VERSION 5.7 ;
  NOWIREEXTENSIONATPIN ON ;
  DIVIDERCHAR "/" ;
  BUSBITCHARS "[]" ;
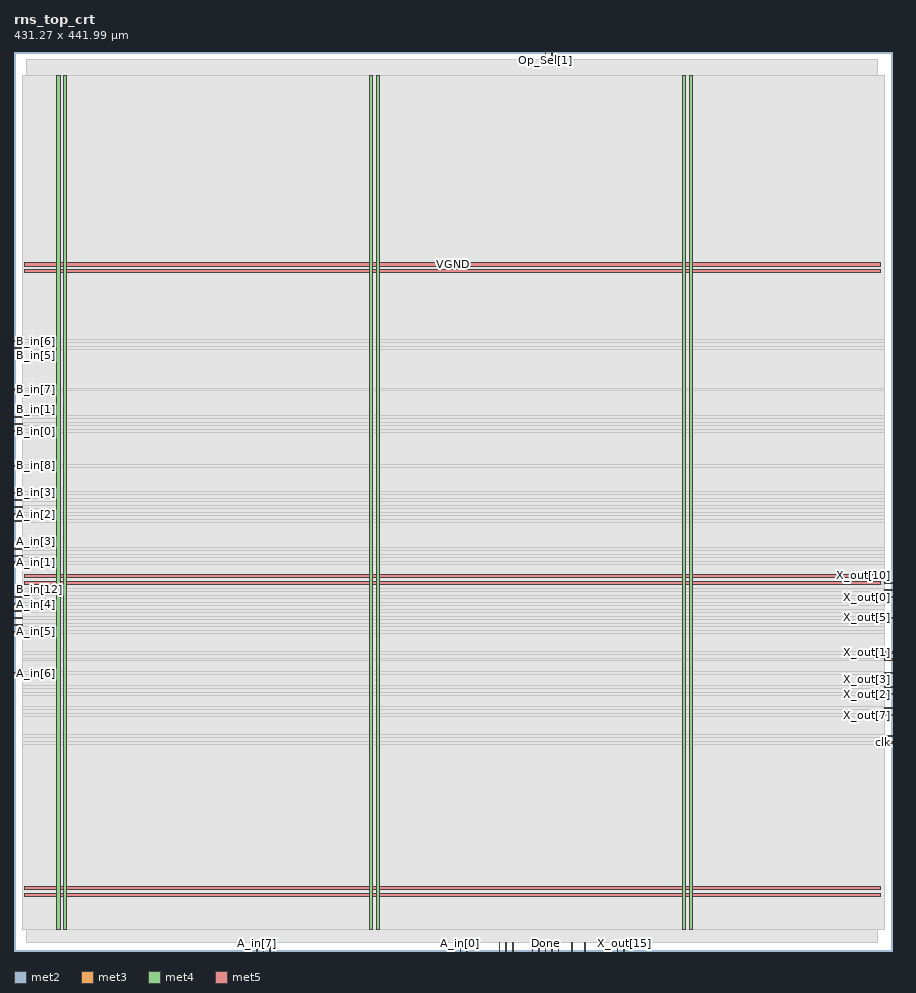
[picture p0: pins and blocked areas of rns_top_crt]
MACRO rns_top_crt
  CLASS BLOCK ;
  FOREIGN rns_top_crt ;
  ORIGIN 0.000 0.000 ;
  SIZE 431.270 BY 441.990 ;
  PIN A_in[0]
    DIRECTION INPUT ;
    USE SIGNAL ;
    ANTENNAGATEAREA 0.631200 ;
    ANTENNADIFFAREA 0.434700 ;
    PORT
      LAYER met2 ;
        RECT 219.050 0.000 219.330 4.000 ;
    END
  END A_in[0]
  PIN A_in[10]
    DIRECTION INPUT ;
    USE SIGNAL ;
    ANTENNAGATEAREA 0.631200 ;
    ANTENNADIFFAREA 0.434700 ;
    PORT
      LAYER met2 ;
        RECT 222.270 0.000 222.550 4.000 ;
    END
  END A_in[10]
  PIN A_in[11]
    DIRECTION INPUT ;
    USE SIGNAL ;
    ANTENNAGATEAREA 0.631200 ;
    ANTENNADIFFAREA 0.434700 ;
    PORT
      LAYER met2 ;
        RECT 238.370 0.000 238.650 4.000 ;
    END
  END A_in[11]
  PIN A_in[12]
    DIRECTION INPUT ;
    USE SIGNAL ;
    ANTENNAGATEAREA 0.631200 ;
    ANTENNADIFFAREA 0.434700 ;
    PORT
      LAYER met2 ;
        RECT 244.810 0.000 245.090 4.000 ;
    END
  END A_in[12]
  PIN A_in[13]
    DIRECTION INPUT ;
    USE SIGNAL ;
    ANTENNAGATEAREA 0.631200 ;
    ANTENNADIFFAREA 0.434700 ;
    PORT
      LAYER met2 ;
        RECT 257.690 0.000 257.970 4.000 ;
    END
  END A_in[13]
  PIN A_in[14]
    DIRECTION INPUT ;
    USE SIGNAL ;
    ANTENNAGATEAREA 0.631200 ;
    ANTENNADIFFAREA 0.434700 ;
    PORT
      LAYER met2 ;
        RECT 241.590 0.000 241.870 4.000 ;
    END
  END A_in[14]
  PIN A_in[15]
    DIRECTION INPUT ;
    USE SIGNAL ;
    ANTENNAGATEAREA 0.631200 ;
    ANTENNADIFFAREA 0.434700 ;
    PORT
      LAYER met2 ;
        RECT 254.470 0.000 254.750 4.000 ;
    END
  END A_in[15]
  PIN A_in[1]
    DIRECTION INPUT ;
    USE SIGNAL ;
    ANTENNAGATEAREA 0.631200 ;
    ANTENNADIFFAREA 0.434700 ;
    PORT
      LAYER met3 ;
        RECT 0.000 190.440 4.000 191.040 ;
    END
  END A_in[1]
  PIN A_in[2]
    DIRECTION INPUT ;
    USE SIGNAL ;
    ANTENNAGATEAREA 0.631200 ;
    ANTENNADIFFAREA 0.434700 ;
    PORT
      LAYER met3 ;
        RECT 0.000 214.240 4.000 214.840 ;
    END
  END A_in[2]
  PIN A_in[3]
    DIRECTION INPUT ;
    USE SIGNAL ;
    ANTENNAGATEAREA 0.631200 ;
    ANTENNADIFFAREA 0.434700 ;
    PORT
      LAYER met3 ;
        RECT 0.000 197.240 4.000 197.840 ;
    END
  END A_in[3]
  PIN A_in[4]
    DIRECTION INPUT ;
    USE SIGNAL ;
    ANTENNAGATEAREA 0.631200 ;
    ANTENNADIFFAREA 0.434700 ;
    PORT
      LAYER met3 ;
        RECT 0.000 170.040 4.000 170.640 ;
    END
  END A_in[4]
  PIN A_in[5]
    DIRECTION INPUT ;
    USE SIGNAL ;
    ANTENNAGATEAREA 0.631200 ;
    ANTENNADIFFAREA 0.434700 ;
    PORT
      LAYER met3 ;
        RECT 0.000 156.440 4.000 157.040 ;
    END
  END A_in[5]
  PIN A_in[6]
    DIRECTION INPUT ;
    USE SIGNAL ;
    ANTENNAGATEAREA 0.631200 ;
    ANTENNADIFFAREA 0.434700 ;
    PORT
      LAYER met3 ;
        RECT 0.000 136.040 4.000 136.640 ;
    END
  END A_in[6]
  PIN A_in[7]
    DIRECTION INPUT ;
    USE SIGNAL ;
    ANTENNAGATEAREA 0.631200 ;
    ANTENNADIFFAREA 0.434700 ;
    PORT
      LAYER met2 ;
        RECT 119.230 0.000 119.510 4.000 ;
    END
  END A_in[7]
  PIN A_in[8]
    DIRECTION INPUT ;
    USE SIGNAL ;
    ANTENNAGATEAREA 0.631200 ;
    ANTENNADIFFAREA 0.434700 ;
    PORT
      LAYER met2 ;
        RECT 125.670 0.000 125.950 4.000 ;
    END
  END A_in[8]
  PIN A_in[9]
    DIRECTION INPUT ;
    USE SIGNAL ;
    ANTENNAGATEAREA 0.631200 ;
    ANTENNADIFFAREA 0.434700 ;
    PORT
      LAYER met2 ;
        RECT 122.450 0.000 122.730 4.000 ;
    END
  END A_in[9]
  PIN B_in[0]
    DIRECTION INPUT ;
    USE SIGNAL ;
    ANTENNAGATEAREA 0.631200 ;
    ANTENNADIFFAREA 0.434700 ;
    PORT
      LAYER met3 ;
        RECT 0.000 255.040 4.000 255.640 ;
    END
  END B_in[0]
  PIN B_in[10]
    DIRECTION INPUT ;
    USE SIGNAL ;
    ANTENNAGATEAREA 0.631200 ;
    ANTENNADIFFAREA 0.434700 ;
    PORT
      LAYER met3 ;
        RECT 0.000 210.840 4.000 211.440 ;
    END
  END B_in[10]
  PIN B_in[11]
    DIRECTION INPUT ;
    USE SIGNAL ;
    ANTENNAGATEAREA 0.631200 ;
    ANTENNADIFFAREA 0.434700 ;
    PORT
      LAYER met3 ;
        RECT 0.000 193.840 4.000 194.440 ;
    END
  END B_in[11]
  PIN B_in[12]
    DIRECTION INPUT ;
    USE SIGNAL ;
    ANTENNAGATEAREA 0.631200 ;
    ANTENNADIFFAREA 0.434700 ;
    PORT
      LAYER met3 ;
        RECT 0.000 173.440 4.000 174.040 ;
    END
  END B_in[12]
  PIN B_in[13]
    DIRECTION INPUT ;
    USE SIGNAL ;
    ANTENNAGATEAREA 0.631200 ;
    ANTENNADIFFAREA 0.434700 ;
    PORT
      LAYER met3 ;
        RECT 0.000 163.240 4.000 163.840 ;
    END
  END B_in[13]
  PIN B_in[14]
    DIRECTION INPUT ;
    USE SIGNAL ;
    ANTENNAGATEAREA 0.631200 ;
    ANTENNADIFFAREA 0.434700 ;
    PORT
      LAYER met3 ;
        RECT 0.000 166.640 4.000 167.240 ;
    END
  END B_in[14]
  PIN B_in[15]
    DIRECTION INPUT ;
    USE SIGNAL ;
    ANTENNAGATEAREA 0.631200 ;
    ANTENNADIFFAREA 0.434700 ;
    PORT
      LAYER met3 ;
        RECT 0.000 159.840 4.000 160.440 ;
    END
  END B_in[15]
  PIN B_in[1]
    DIRECTION INPUT ;
    USE SIGNAL ;
    ANTENNAGATEAREA 0.631200 ;
    ANTENNADIFFAREA 0.434700 ;
    PORT
      LAYER met3 ;
        RECT 0.000 261.840 4.000 262.440 ;
    END
  END B_in[1]
  PIN B_in[2]
    DIRECTION INPUT ;
    USE SIGNAL ;
    ANTENNAGATEAREA 0.631200 ;
    ANTENNADIFFAREA 0.434700 ;
    PORT
      LAYER met3 ;
        RECT 0.000 258.440 4.000 259.040 ;
    END
  END B_in[2]
  PIN B_in[3]
    DIRECTION INPUT ;
    USE SIGNAL ;
    ANTENNAGATEAREA 0.631200 ;
    ANTENNADIFFAREA 0.434700 ;
    PORT
      LAYER met3 ;
        RECT 0.000 221.040 4.000 221.640 ;
    END
  END B_in[3]
  PIN B_in[4]
    DIRECTION INPUT ;
    USE SIGNAL ;
    ANTENNAGATEAREA 0.631200 ;
    ANTENNADIFFAREA 0.434700 ;
    PORT
      LAYER met3 ;
        RECT 0.000 217.640 4.000 218.240 ;
    END
  END B_in[4]
  PIN B_in[5]
    DIRECTION INPUT ;
    USE SIGNAL ;
    ANTENNAGATEAREA 0.631200 ;
    ANTENNADIFFAREA 0.434700 ;
    PORT
      LAYER met3 ;
        RECT 0.000 295.840 4.000 296.440 ;
    END
  END B_in[5]
  PIN B_in[6]
    DIRECTION INPUT ;
    USE SIGNAL ;
    ANTENNAGATEAREA 0.631200 ;
    ANTENNADIFFAREA 0.434700 ;
    PORT
      LAYER met3 ;
        RECT 0.000 299.240 4.000 299.840 ;
    END
  END B_in[6]
  PIN B_in[7]
    DIRECTION INPUT ;
    USE SIGNAL ;
    ANTENNAGATEAREA 0.631200 ;
    ANTENNADIFFAREA 0.434700 ;
    PORT
      LAYER met3 ;
        RECT 0.000 275.440 4.000 276.040 ;
    END
  END B_in[7]
  PIN B_in[8]
    DIRECTION INPUT ;
    USE SIGNAL ;
    ANTENNAGATEAREA 0.631200 ;
    ANTENNADIFFAREA 0.434700 ;
    PORT
      LAYER met3 ;
        RECT 0.000 238.040 4.000 238.640 ;
    END
  END B_in[8]
  PIN B_in[9]
    DIRECTION INPUT ;
    USE SIGNAL ;
    ANTENNAGATEAREA 0.631200 ;
    ANTENNADIFFAREA 0.434700 ;
    PORT
      LAYER met3 ;
        RECT 0.000 224.440 4.000 225.040 ;
    END
  END B_in[9]
  PIN Done
    DIRECTION OUTPUT ;
    USE SIGNAL ;
    ANTENNADIFFAREA 0.340600 ;
    PORT
      LAYER met2 ;
        RECT 260.910 0.000 261.190 4.000 ;
    END
  END Done
  PIN Op_Sel[0]
    DIRECTION INPUT ;
    USE SIGNAL ;
    ANTENNAGATEAREA 0.560700 ;
    ANTENNADIFFAREA 0.434700 ;
    PORT
      LAYER met2 ;
        RECT 264.130 437.990 264.410 441.990 ;
    END
  END Op_Sel[0]
  PIN Op_Sel[1]
    DIRECTION INPUT ;
    USE SIGNAL ;
    ANTENNAGATEAREA 0.560700 ;
    ANTENNADIFFAREA 0.434700 ;
    PORT
      LAYER met2 ;
        RECT 260.910 437.990 261.190 441.990 ;
    END
  END Op_Sel[1]
  PIN Start
    DIRECTION INPUT ;
    USE SIGNAL ;
    ANTENNAGATEAREA 0.631200 ;
    ANTENNADIFFAREA 0.434700 ;
    PORT
      LAYER met2 ;
        RECT 264.130 0.000 264.410 4.000 ;
    END
  END Start
  PIN VGND
    DIRECTION INOUT ;
    USE GROUND ;
    PORT
      LAYER met4 ;
        RECT 24.340 10.640 25.940 430.000 ;
    END
    PORT
      LAYER met4 ;
        RECT 177.940 10.640 179.540 430.000 ;
    END
    PORT
      LAYER met4 ;
        RECT 331.540 10.640 333.140 430.000 ;
    END
    PORT
      LAYER met5 ;
        RECT 5.280 30.030 425.740 31.630 ;
    END
    PORT
      LAYER met5 ;
        RECT 5.280 183.210 425.740 184.810 ;
    END
    PORT
      LAYER met5 ;
        RECT 5.280 336.390 425.740 337.990 ;
    END
  END VGND
  PIN VPWR
    DIRECTION INOUT ;
    USE POWER ;
    PORT
      LAYER met4 ;
        RECT 21.040 10.640 22.640 430.000 ;
    END
    PORT
      LAYER met4 ;
        RECT 174.640 10.640 176.240 430.000 ;
    END
    PORT
      LAYER met4 ;
        RECT 328.240 10.640 329.840 430.000 ;
    END
    PORT
      LAYER met5 ;
        RECT 5.280 26.730 425.740 28.330 ;
    END
    PORT
      LAYER met5 ;
        RECT 5.280 179.910 425.740 181.510 ;
    END
    PORT
      LAYER met5 ;
        RECT 5.280 333.090 425.740 334.690 ;
    END
  END VPWR
  PIN X_out[0]
    DIRECTION OUTPUT ;
    USE SIGNAL ;
    ANTENNADIFFAREA 0.340600 ;
    PORT
      LAYER met3 ;
        RECT 427.270 173.440 431.270 174.040 ;
    END
  END X_out[0]
  PIN X_out[10]
    DIRECTION OUTPUT ;
    USE SIGNAL ;
    ANTENNADIFFAREA 0.340600 ;
    PORT
      LAYER met3 ;
        RECT 427.270 180.240 431.270 180.840 ;
    END
  END X_out[10]
  PIN X_out[11]
    DIRECTION OUTPUT ;
    USE SIGNAL ;
    ANTENNADIFFAREA 0.340600 ;
    PORT
      LAYER met2 ;
        RECT 267.350 0.000 267.630 4.000 ;
    END
  END X_out[11]
  PIN X_out[12]
    DIRECTION OUTPUT ;
    USE SIGNAL ;
    ANTENNADIFFAREA 0.340600 ;
    PORT
      LAYER met2 ;
        RECT 280.230 0.000 280.510 4.000 ;
    END
  END X_out[12]
  PIN X_out[13]
    DIRECTION OUTPUT ;
    USE SIGNAL ;
    ANTENNADIFFAREA 0.340600 ;
    PORT
      LAYER met2 ;
        RECT 273.790 0.000 274.070 4.000 ;
    END
  END X_out[13]
  PIN X_out[14]
    DIRECTION OUTPUT ;
    USE SIGNAL ;
    ANTENNADIFFAREA 0.340600 ;
    PORT
      LAYER met2 ;
        RECT 296.330 0.000 296.610 4.000 ;
    END
  END X_out[14]
  PIN X_out[15]
    DIRECTION OUTPUT ;
    USE SIGNAL ;
    ANTENNADIFFAREA 0.340600 ;
    PORT
      LAYER met2 ;
        RECT 299.550 0.000 299.830 4.000 ;
    END
  END X_out[15]
  PIN X_out[1]
    DIRECTION OUTPUT ;
    USE SIGNAL ;
    ANTENNADIFFAREA 0.340600 ;
    PORT
      LAYER met3 ;
        RECT 427.270 146.240 431.270 146.840 ;
    END
  END X_out[1]
  PIN X_out[2]
    DIRECTION OUTPUT ;
    USE SIGNAL ;
    ANTENNADIFFAREA 0.340600 ;
    PORT
      LAYER met3 ;
        RECT 427.270 125.840 431.270 126.440 ;
    END
  END X_out[2]
  PIN X_out[3]
    DIRECTION OUTPUT ;
    USE SIGNAL ;
    ANTENNADIFFAREA 0.340600 ;
    PORT
      LAYER met3 ;
        RECT 427.270 129.240 431.270 129.840 ;
    END
  END X_out[3]
  PIN X_out[4]
    DIRECTION OUTPUT ;
    USE SIGNAL ;
    ANTENNADIFFAREA 0.340600 ;
    PORT
      LAYER met3 ;
        RECT 427.270 176.840 431.270 177.440 ;
    END
  END X_out[4]
  PIN X_out[5]
    DIRECTION OUTPUT ;
    USE SIGNAL ;
    ANTENNADIFFAREA 0.340600 ;
    PORT
      LAYER met3 ;
        RECT 427.270 163.240 431.270 163.840 ;
    END
  END X_out[5]
  PIN X_out[6]
    DIRECTION OUTPUT ;
    USE SIGNAL ;
    ANTENNADIFFAREA 0.340600 ;
    PORT
      LAYER met3 ;
        RECT 427.270 142.840 431.270 143.440 ;
    END
  END X_out[6]
  PIN X_out[7]
    DIRECTION OUTPUT ;
    USE SIGNAL ;
    ANTENNADIFFAREA 0.340600 ;
    PORT
      LAYER met3 ;
        RECT 427.270 119.040 431.270 119.640 ;
    END
  END X_out[7]
  PIN X_out[8]
    DIRECTION OUTPUT ;
    USE SIGNAL ;
    ANTENNADIFFAREA 0.340600 ;
    PORT
      LAYER met3 ;
        RECT 427.270 136.040 431.270 136.640 ;
    END
  END X_out[8]
  PIN X_out[9]
    DIRECTION OUTPUT ;
    USE SIGNAL ;
    ANTENNADIFFAREA 0.340600 ;
    PORT
      LAYER met3 ;
        RECT 427.270 115.640 431.270 116.240 ;
    END
  END X_out[9]
  PIN clk
    DIRECTION INPUT ;
    USE SIGNAL ;
    ANTENNAGATEAREA 1.286700 ;
    ANTENNADIFFAREA 0.434700 ;
    PORT
      LAYER met3 ;
        RECT 427.270 102.040 431.270 102.640 ;
    END
  END clk
  PIN rst_n
    DIRECTION INPUT ;
    USE SIGNAL ;
    ANTENNAGATEAREA 1.286700 ;
    ANTENNADIFFAREA 0.434700 ;
    PORT
      LAYER met3 ;
        RECT 427.270 105.440 431.270 106.040 ;
    END
  END rst_n
  OBS
      LAYER nwell ;
        RECT 5.330 10.795 425.690 429.845 ;
      LAYER li1 ;
        RECT 5.520 10.795 425.500 429.845 ;
      LAYER met1 ;
        RECT 5.520 10.640 425.500 430.000 ;
      LAYER met2 ;
        RECT 6.070 437.710 260.630 437.990 ;
        RECT 261.470 437.710 263.850 437.990 ;
        RECT 264.690 437.710 424.030 437.990 ;
        RECT 6.070 4.280 424.030 437.710 ;
        RECT 6.070 4.000 118.950 4.280 ;
        RECT 119.790 4.000 122.170 4.280 ;
        RECT 123.010 4.000 125.390 4.280 ;
        RECT 126.230 4.000 218.770 4.280 ;
        RECT 219.610 4.000 221.990 4.280 ;
        RECT 222.830 4.000 238.090 4.280 ;
        RECT 238.930 4.000 241.310 4.280 ;
        RECT 242.150 4.000 244.530 4.280 ;
        RECT 245.370 4.000 254.190 4.280 ;
        RECT 255.030 4.000 257.410 4.280 ;
        RECT 258.250 4.000 260.630 4.280 ;
        RECT 261.470 4.000 263.850 4.280 ;
        RECT 264.690 4.000 267.070 4.280 ;
        RECT 267.910 4.000 273.510 4.280 ;
        RECT 274.350 4.000 279.950 4.280 ;
        RECT 280.790 4.000 296.050 4.280 ;
        RECT 296.890 4.000 299.270 4.280 ;
        RECT 300.110 4.000 424.030 4.280 ;
      LAYER met3 ;
        RECT 4.000 300.240 427.270 429.925 ;
        RECT 4.400 298.840 427.270 300.240 ;
        RECT 4.000 296.840 427.270 298.840 ;
        RECT 4.400 295.440 427.270 296.840 ;
        RECT 4.000 276.440 427.270 295.440 ;
        RECT 4.400 275.040 427.270 276.440 ;
        RECT 4.000 262.840 427.270 275.040 ;
        RECT 4.400 261.440 427.270 262.840 ;
        RECT 4.000 259.440 427.270 261.440 ;
        RECT 4.400 258.040 427.270 259.440 ;
        RECT 4.000 256.040 427.270 258.040 ;
        RECT 4.400 254.640 427.270 256.040 ;
        RECT 4.000 239.040 427.270 254.640 ;
        RECT 4.400 237.640 427.270 239.040 ;
        RECT 4.000 225.440 427.270 237.640 ;
        RECT 4.400 224.040 427.270 225.440 ;
        RECT 4.000 222.040 427.270 224.040 ;
        RECT 4.400 220.640 427.270 222.040 ;
        RECT 4.000 218.640 427.270 220.640 ;
        RECT 4.400 217.240 427.270 218.640 ;
        RECT 4.000 215.240 427.270 217.240 ;
        RECT 4.400 213.840 427.270 215.240 ;
        RECT 4.000 211.840 427.270 213.840 ;
        RECT 4.400 210.440 427.270 211.840 ;
        RECT 4.000 198.240 427.270 210.440 ;
        RECT 4.400 196.840 427.270 198.240 ;
        RECT 4.000 194.840 427.270 196.840 ;
        RECT 4.400 193.440 427.270 194.840 ;
        RECT 4.000 191.440 427.270 193.440 ;
        RECT 4.400 190.040 427.270 191.440 ;
        RECT 4.000 181.240 427.270 190.040 ;
        RECT 4.000 179.840 426.870 181.240 ;
        RECT 4.000 177.840 427.270 179.840 ;
        RECT 4.000 176.440 426.870 177.840 ;
        RECT 4.000 174.440 427.270 176.440 ;
        RECT 4.400 173.040 426.870 174.440 ;
        RECT 4.000 171.040 427.270 173.040 ;
        RECT 4.400 169.640 427.270 171.040 ;
        RECT 4.000 167.640 427.270 169.640 ;
        RECT 4.400 166.240 427.270 167.640 ;
        RECT 4.000 164.240 427.270 166.240 ;
        RECT 4.400 162.840 426.870 164.240 ;
        RECT 4.000 160.840 427.270 162.840 ;
        RECT 4.400 159.440 427.270 160.840 ;
        RECT 4.000 157.440 427.270 159.440 ;
        RECT 4.400 156.040 427.270 157.440 ;
        RECT 4.000 147.240 427.270 156.040 ;
        RECT 4.000 145.840 426.870 147.240 ;
        RECT 4.000 143.840 427.270 145.840 ;
        RECT 4.000 142.440 426.870 143.840 ;
        RECT 4.000 137.040 427.270 142.440 ;
        RECT 4.400 135.640 426.870 137.040 ;
        RECT 4.000 130.240 427.270 135.640 ;
        RECT 4.000 128.840 426.870 130.240 ;
        RECT 4.000 126.840 427.270 128.840 ;
        RECT 4.000 125.440 426.870 126.840 ;
        RECT 4.000 120.040 427.270 125.440 ;
        RECT 4.000 118.640 426.870 120.040 ;
        RECT 4.000 116.640 427.270 118.640 ;
        RECT 4.000 115.240 426.870 116.640 ;
        RECT 4.000 106.440 427.270 115.240 ;
        RECT 4.000 105.040 426.870 106.440 ;
        RECT 4.000 103.040 427.270 105.040 ;
        RECT 4.000 101.640 426.870 103.040 ;
        RECT 4.000 10.715 427.270 101.640 ;
  END
END rns_top_crt
END LIBRARY

